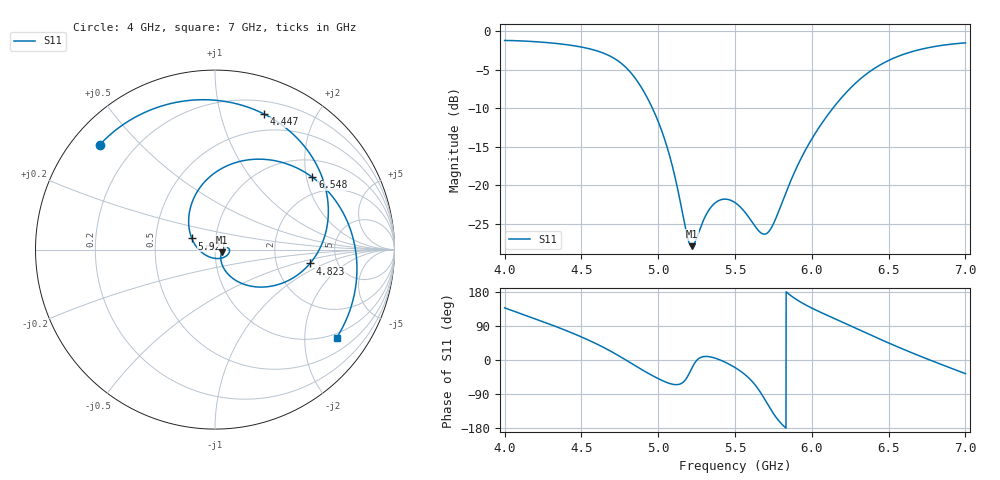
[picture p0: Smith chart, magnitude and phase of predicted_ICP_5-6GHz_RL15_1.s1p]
! ICP-predicted S11, target 5.000-6.000 GHz at -15 dB. Complex ensemble mean (passive and causal);
! its |S11| can differ slightly from the dB-domain mean reported in designs.csv.
!  Air_gap = 1.92mm
!  W_Patch = 13.39mm
!  L_Patch = 16.52mm
!  Sx = 0.46mm
!  Sy = 4.3mm
!  W_Patch1 = 13.54mm
!  WS = 1.11mm
!  Curve_Amp1 = 2.35mm
!  Extra = 3.44mm
# GHz S MA R 50
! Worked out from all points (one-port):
!   3001 points, 4 GHz to 7 GHz, reference 50 ohm
!   lowest |S11| = -27.9 dB at 5.218 GHz (marker M1), VSWR 1.08, Z = 53.9 - j1.64 ohm
!   |S11| at or under -10 dB: 4.962 GHz to 6.137 GHz (1.175 GHz wide, 21.2 % of centre)
!   S11 on the Smith chart (normalised r, x): 4 GHz: 0.08, +0.38; 4.447 GHz: 0.32, +1.38; 4.823 GHz: 3.14, -0.68; 5.921 GHz: 0.77, +0.10; 6.548 GHz: 1.46, +2.17; 7 GHz: 0.86, -2.84
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4  0.8678 137.7
4.197  0.8523 109.0
4.375  0.8216 81.8
4.447  0.8033 70.0
4.534  0.7739 54.8
4.621  0.7322 38.0
4.75  0.6278 9.5
4.823  0.5347 -8.3
4.886  0.4378 -23.7
4.951  0.3341 -38.7
5.047  0.1917 -57.9
5.125  0.0965 -65.0
5.187  0.04758 -46.5
5.218  0.04041 -22.1
5.36  0.07536 6.1
5.5  0.0774 -19.9
5.702  0.04859 -109.6
5.754  0.05746 -143.7
5.875  0.1142 166.5
5.921  0.1434 154.3
6.1  0.2822 118.0
6.25  0.4249 90.7
6.402  0.5671 62.6
6.548  0.6763 36.6
6.625  0.7208 23.4
6.718  0.7636 8.1
6.809  0.7956 -6.4
7  0.8372 -36.0
